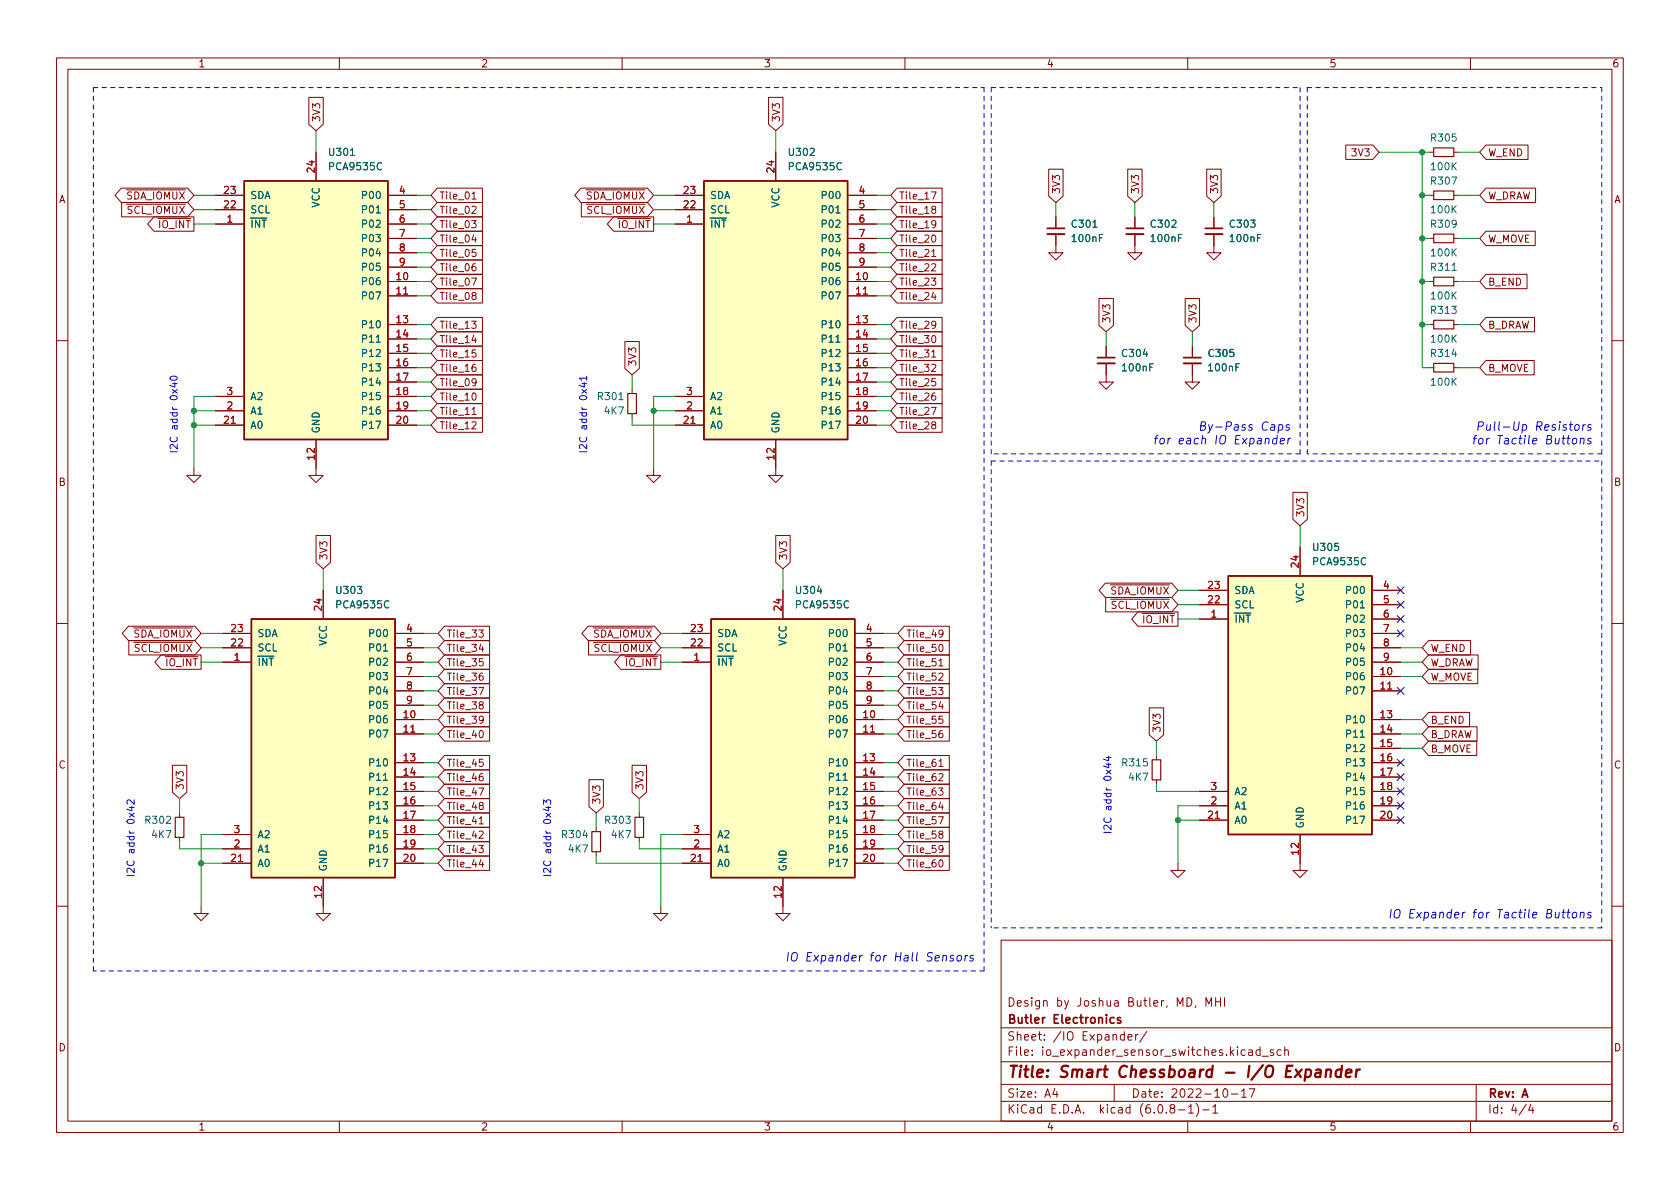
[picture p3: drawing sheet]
<svg xmlns="http://www.w3.org/2000/svg" width="297mm" height="210mm" viewBox="0 0 297 210" stroke-linecap="round" stroke-linejoin="round" font-family="sans-serif">
<defs><g id="words">
<text font-size="2.8" fill="#840000" x="178" y="190.6">Title: Smart Chessboard - I/O Expander</text>
<g font-size="2.1" fill="#0000c2">
<text x="214.7" y="76.2">By-Pass Caps</text>
<text x="264.5" y="76.2">Pull-Up Resistors</text>
<text x="207.6" y="78.6">for each IO Expander</text>
<text x="263.5" y="78.6">for Tactile Buttons</text>
<text x="250.6" y="162.4">IO Expander for Tactile Buttons</text>
<text x="143.8" y="170">IO Expander for Hall Sensors</text>
</g>
<g font-size="2.1" fill="#840000">
<text x="178" y="178">Design by Joshua Butler, MD, MHI</text>
<text x="178" y="184">Sheet: /IO Expander/</text>
<text x="178" y="181">Butler Electronics</text>
<text x="178" y="186.7">File: io_expander_sensor_switches.kicad_sch</text>
<text x="178" y="196.9">KiCad E.D.A. kicad (6.0.8-1)-1</text>
<text x="178" y="194.1">Size: A4</text>
<text x="200" y="194.1">Date: 2022-10-17</text>
<text x="263" y="194.1">Rev: A</text>
<text x="263" y="196.9">Id: 4/4</text>
</g>
<g font-size="1.8" fill="#840000">
<text x="35" y="11.9">1</text>
<text x="85" y="11.9">2</text>
<text x="135" y="11.9">3</text>
<text x="185" y="11.9">4</text>
<text x="235" y="11.9">5</text>
<text x="285" y="11.9">6</text>
<text x="56.6" y="21.7" transform="rotate(-90 56.6 21.7)">3V3</text>
<text x="137.9" y="21.7" transform="rotate(-90 137.9 21.7)">3V3</text>
<text x="239.3" y="27.6">3V3</text>
<text x="263.1" y="27.6">W_END</text>
<text x="10.3" y="35.9">A</text>
<text x="21" y="35.3">~{SDA_IOMUX}</text>
<text x="77.6" y="35.3">Tile_01</text>
<text x="102.2" y="35.3">~{SDA_IOMUX}</text>
<text x="158.9" y="35.3">Tile_17</text>
<text x="187.4" y="34.4" transform="rotate(-90 187.4 34.4)">3V3</text>
<text x="201.4" y="34.4" transform="rotate(-90 201.4 34.4)">3V3</text>
<text x="215.4" y="34.4" transform="rotate(-90 215.4 34.4)">3V3</text>
<text x="263.1" y="35.3">W_DRAW</text>
<text x="285.3" y="35.9">A</text>
<text x="21.2" y="37.8">~{SCL_IOMUX}</text>
<text x="26.7" y="40.3">~{IO_INT}</text>
<text x="77.6" y="40.3">Tile_03</text>
<text x="77.6" y="37.8">Tile_02</text>
<text x="102.4" y="37.8">~{SCL_IOMUX}</text>
<text x="108" y="40.3">~{IO_INT}</text>
<text x="158.9" y="37.8">Tile_18</text>
<text x="158.9" y="40.3">Tile_19</text>
<text x="77.6" y="42.9">Tile_04</text>
<text x="77.6" y="45.4">Tile_05</text>
<text x="77.6" y="48">Tile_06</text>
<text x="158.9" y="42.9">Tile_20</text>
<text x="158.9" y="45.4">Tile_21</text>
<text x="158.9" y="48">Tile_22</text>
<text x="263.1" y="42.9">W_MOVE</text>
<text x="77.6" y="50.5">Tile_07</text>
<text x="77.6" y="53">Tile_08</text>
<text x="158.9" y="50.5">Tile_23</text>
<text x="158.9" y="53">Tile_24</text>
<text x="263.1" y="50.5">B_END</text>
<text x="77.6" y="58.1">Tile_13</text>
<text x="158.9" y="58.1">Tile_29</text>
<text x="196.3" y="57.2" transform="rotate(-90 196.3 57.2)">3V3</text>
<text x="211.5" y="57.2" transform="rotate(-90 211.5 57.2)">3V3</text>
<text x="263.1" y="58.1">B_DRAW</text>
<text x="77.6" y="65.7">Tile_16</text>
<text x="77.6" y="60.7">Tile_14</text>
<text x="77.6" y="63.2">Tile_15</text>
<text x="112.5" y="64.9" transform="rotate(-90 112.5 64.9)">3V3</text>
<text x="158.9" y="60.7">Tile_30</text>
<text x="158.9" y="63.2">Tile_31</text>
<text x="158.9" y="65.7">Tile_32</text>
<text x="263.1" y="65.7">B_MOVE</text>
<text x="77.6" y="68.3">Tile_09</text>
<text x="77.6" y="70.8">Tile_10</text>
<text x="158.9" y="68.3">Tile_25</text>
<text x="158.9" y="70.8">Tile_26</text>
<text x="77.6" y="73.4">Tile_11</text>
<text x="77.6" y="75.9">Tile_12</text>
<text x="158.9" y="73.4">Tile_27</text>
<text x="158.9" y="75.9">Tile_28</text>
<text x="10.3" y="85.9">B</text>
<text x="285.3" y="85.9">B</text>
<text x="230.6" y="91.5" transform="rotate(-90 230.6 91.5)">3V3</text>
<text x="57.9" y="99.1" transform="rotate(-90 57.9 99.1)">3V3</text>
<text x="139.2" y="99.1" transform="rotate(-90 139.2 99.1)">3V3</text>
<text x="195" y="105.1">~{SDA_IOMUX}</text>
<text x="195.2" y="107.7">~{SCL_IOMUX}</text>
<text x="22.2" y="112.7">~{SDA_IOMUX}</text>
<text x="78.9" y="112.7">Tile_33</text>
<text x="103.5" y="112.7">~{SDA_IOMUX}</text>
<text x="160.2" y="112.7">Tile_49</text>
<text x="200.7" y="110.2">~{IO_INT}</text>
<text x="22.4" y="115.3">~{SCL_IOMUX}</text>
<text x="28" y="117.8">~{IO_INT}</text>
<text x="78.9" y="115.3">Tile_34</text>
<text x="78.9" y="117.8">Tile_35</text>
<text x="103.7" y="115.3">~{SCL_IOMUX}</text>
<text x="109.3" y="117.8">~{IO_INT}</text>
<text x="160.2" y="115.3">Tile_50</text>
<text x="160.2" y="117.8">Tile_51</text>
<text x="252.9" y="117.8">W_DRAW</text>
<text x="252.9" y="115.3">W_END</text>
<text x="78.9" y="120.4">Tile_36</text>
<text x="78.9" y="125.4">Tile_38</text>
<text x="78.9" y="122.9">Tile_37</text>
<text x="160.2" y="125.4">Tile_54</text>
<text x="160.2" y="122.9">Tile_53</text>
<text x="160.2" y="120.4">Tile_52</text>
<text x="252.9" y="120.4">W_MOVE</text>
<text x="78.9" y="128">Tile_39</text>
<text x="78.9" y="130.5">Tile_40</text>
<text x="160.2" y="130.5">Tile_56</text>
<text x="160.2" y="128">Tile_55</text>
<text x="205.2" y="129.6" transform="rotate(-90 205.2 129.6)">3V3</text>
<text x="252.9" y="128">B_END</text>
<text x="252.9" y="130.5">B_DRAW</text>
<text x="10.3" y="135.9">C</text>
<text x="78.9" y="135.6">Tile_45</text>
<text x="160.2" y="135.6">Tile_61</text>
<text x="252.9" y="133.1">B_MOVE</text>
<text x="285.3" y="135.9">C</text>
<text x="32.5" y="139.8" transform="rotate(-90 32.5 139.8)">3V3</text>
<text x="78.9" y="138.1">Tile_46</text>
<text x="78.9" y="143.2">Tile_48</text>
<text x="78.9" y="140.7">Tile_47</text>
<text x="106.1" y="142.3" transform="rotate(-90 106.1 142.3)">3V3</text>
<text x="113.8" y="139.8" transform="rotate(-90 113.8 139.8)">3V3</text>
<text x="160.2" y="138.1">Tile_62</text>
<text x="160.2" y="143.2">Tile_64</text>
<text x="160.2" y="140.7">Tile_63</text>
<text x="78.9" y="148.3">Tile_42</text>
<text x="78.9" y="145.8">Tile_41</text>
<text x="160.2" y="148.3">Tile_58</text>
<text x="160.2" y="145.8">Tile_57</text>
<text x="78.9" y="153.4">Tile_44</text>
<text x="78.9" y="150.8">Tile_43</text>
<text x="160.2" y="153.4">Tile_60</text>
<text x="160.2" y="150.8">Tile_59</text>
<text x="10.3" y="185.9">D</text>
<text x="285.3" y="185.9">D</text>
<text x="35" y="199.9">1</text>
<text x="85" y="199.9">2</text>
<text x="135" y="199.9">3</text>
<text x="185" y="199.9">4</text>
<text x="235" y="199.9">5</text>
<text x="285" y="199.9">6</text>
</g>
<g font-size="1.8" fill="#006464">
<text x="58.3" y="27.6">U301</text>
<text x="139.6" y="27.6">U302</text>
<text x="253.2" y="25">R305</text>
<text x="44.2" y="35.2">SDA</text>
<text x="58.4" y="30.1">PCA9535C</text>
<text x="64.4" y="35.2">P00</text>
<text x="125.5" y="35.2">SDA</text>
<text x="139.7" y="30.1">PCA9535C</text>
<text x="145.7" y="35.2">P00</text>
<text x="253.2" y="32.6">R307</text>
<text x="253.2" y="30.1">100K</text>
<text x="44.2" y="40.3">~{INT}</text>
<text x="44.2" y="37.7">SCL</text>
<text x="56.5" y="36.7" transform="rotate(-90 56.5 36.7)">VCC</text>
<text x="64.4" y="37.7">P01</text>
<text x="64.4" y="40.3">P02</text>
<text x="125.5" y="40.3">~{INT}</text>
<text x="125.5" y="37.7">SCL</text>
<text x="137.8" y="36.7" transform="rotate(-90 137.8 36.7)">VCC</text>
<text x="145.7" y="37.7">P01</text>
<text x="145.7" y="40.3">P02</text>
<text x="189.6" y="40.3">C301</text>
<text x="203.6" y="40.3">C302</text>
<text x="217.6" y="40.3">C303</text>
<text x="253.2" y="37.7">100K</text>
<text x="253.2" y="40.3">R309</text>
<text x="64.4" y="42.8">P03</text>
<text x="64.4" y="45.3">P04</text>
<text x="64.4" y="47.9">P05</text>
<text x="145.7" y="42.8">P03</text>
<text x="145.7" y="45.3">P04</text>
<text x="145.7" y="47.9">P05</text>
<text x="189.7" y="42.8">100nF</text>
<text x="203.7" y="42.8">100nF</text>
<text x="217.6" y="42.8">100nF</text>
<text x="253.2" y="45.3">100K</text>
<text x="253.2" y="47.9">R311</text>
<text x="64.4" y="50.4">P06</text>
<text x="64.4" y="53">P07</text>
<text x="145.7" y="50.4">P06</text>
<text x="145.7" y="53">P07</text>
<text x="253.2" y="53">100K</text>
<text x="64.4" y="58">P10</text>
<text x="145.7" y="58">P10</text>
<text x="253.2" y="55.5">R313</text>
<text x="64.4" y="60.6">P11</text>
<text x="64.4" y="63.1">P12</text>
<text x="64.4" y="65.7">P13</text>
<text x="145.7" y="60.6">P11</text>
<text x="145.7" y="63.1">P12</text>
<text x="145.7" y="65.7">P13</text>
<text x="198.5" y="63.1">C304</text>
<text x="198.6" y="65.7">100nF</text>
<text x="213.8" y="63.1">C305</text>
<text x="213.8" y="65.7">100nF</text>
<text x="253.2" y="60.6">100K</text>
<text x="253.2" y="63.1">R314</text>
<text x="44.2" y="70.7">A2</text>
<text x="64.4" y="68.2">P14</text>
<text x="64.4" y="70.7">P15</text>
<text x="105.8" y="70.7">R301</text>
<text x="125.5" y="70.7">A2</text>
<text x="145.7" y="68.2">P14</text>
<text x="145.7" y="70.7">P15</text>
<text x="253.2" y="68.2">100K</text>
<text x="44.2" y="73.3">A1</text>
<text x="44.2" y="75.8">A0</text>
<text x="56.5" y="76.7" transform="rotate(-90 56.5 76.7)">GND</text>
<text x="64.4" y="73.3">P16</text>
<text x="64.4" y="75.8">P17</text>
<text x="106.9" y="73.3">4K7</text>
<text x="125.5" y="73.3">A1</text>
<text x="125.5" y="75.8">A0</text>
<text x="137.8" y="76.7" transform="rotate(-90 137.8 76.7)">GND</text>
<text x="145.7" y="73.3">P16</text>
<text x="145.7" y="75.8">P17</text>
<text x="232.3" y="97.4">U305</text>
<text x="232.4" y="99.9">PCA9535C</text>
<text x="59.6" y="105">U303</text>
<text x="59.6" y="107.6">PCA9535C</text>
<text x="140.9" y="105">U304</text>
<text x="140.9" y="107.6">PCA9535C</text>
<text x="218.2" y="107.6">SCL</text>
<text x="218.2" y="105">SDA</text>
<text x="230.5" y="106.6" transform="rotate(-90 230.5 106.6)">VCC</text>
<text x="238.4" y="105">P00</text>
<text x="238.4" y="107.6">P01</text>
<text x="45.5" y="112.6">SDA</text>
<text x="65.7" y="112.6">P00</text>
<text x="126.7" y="112.6">SDA</text>
<text x="147" y="112.6">P00</text>
<text x="218.2" y="110.1">~{INT}</text>
<text x="238.4" y="110.1">P02</text>
<text x="238.4" y="112.6">P03</text>
<text x="45.5" y="117.7">~{INT}</text>
<text x="45.5" y="115.2">SCL</text>
<text x="57.8" y="114.2" transform="rotate(-90 57.8 114.2)">VCC</text>
<text x="65.7" y="115.2">P01</text>
<text x="65.7" y="117.7">P02</text>
<text x="126.7" y="117.7">~{INT}</text>
<text x="126.7" y="115.2">SCL</text>
<text x="139.1" y="114.2" transform="rotate(-90 139.1 114.2)">VCC</text>
<text x="147" y="115.2">P01</text>
<text x="147" y="117.7">P02</text>
<text x="238.4" y="115.2">P04</text>
<text x="238.4" y="117.7">P05</text>
<text x="65.7" y="120.3">P03</text>
<text x="65.7" y="122.8">P04</text>
<text x="65.7" y="125.3">P05</text>
<text x="147" y="120.3">P03</text>
<text x="147" y="122.8">P04</text>
<text x="147" y="125.3">P05</text>
<text x="238.4" y="120.3">P06</text>
<text x="238.4" y="122.8">P07</text>
<text x="65.7" y="127.9">P06</text>
<text x="65.7" y="130.4">P07</text>
<text x="147" y="127.9">P06</text>
<text x="147" y="130.4">P07</text>
<text x="238.4" y="127.9">P10</text>
<text x="238.4" y="130.4">P11</text>
<text x="65.7" y="135.5">P10</text>
<text x="147" y="135.5">P10</text>
<text x="198.6" y="135.5">R315</text>
<text x="238.4" y="133">P12</text>
<text x="238.4" y="135.5">P13</text>
<text x="65.7" y="138">P11</text>
<text x="65.7" y="140.6">P12</text>
<text x="65.7" y="143.1">P13</text>
<text x="147" y="138">P11</text>
<text x="147" y="140.6">P12</text>
<text x="147" y="143.1">P13</text>
<text x="199.7" y="138">4K7</text>
<text x="218.2" y="143.1">A1</text>
<text x="218.2" y="140.6">A2</text>
<text x="238.4" y="138">P14</text>
<text x="238.4" y="140.6">P15</text>
<text x="238.4" y="143.1">P16</text>
<text x="25.8" y="145.7">R302</text>
<text x="26.9" y="148.2">4K7</text>
<text x="45.5" y="148.2">A2</text>
<text x="65.7" y="145.7">P14</text>
<text x="65.7" y="148.2">P15</text>
<text x="99.5" y="148.2">R304</text>
<text x="107.1" y="145.7">R303</text>
<text x="108.2" y="148.2">4K7</text>
<text x="126.7" y="148.2">A2</text>
<text x="147" y="145.7">P14</text>
<text x="147" y="148.2">P15</text>
<text x="218.2" y="145.7">A0</text>
<text x="230.5" y="146.6" transform="rotate(-90 230.5 146.6)">GND</text>
<text x="238.4" y="145.7">P17</text>
<text x="45.5" y="150.7">A1</text>
<text x="45.5" y="153.3">A0</text>
<text x="57.8" y="154.2" transform="rotate(-90 57.8 154.2)">GND</text>
<text x="65.7" y="150.7">P16</text>
<text x="65.7" y="153.3">P17</text>
<text x="100.6" y="150.7">4K7</text>
<text x="126.7" y="150.7">A1</text>
<text x="126.7" y="153.3">A0</text>
<text x="139.1" y="154.2" transform="rotate(-90 139.1 154.2)">GND</text>
<text x="147" y="150.7">P16</text>
<text x="147" y="153.3">P17</text>
</g>
<g font-size="1.8" fill="#a90000">
<text x="39.7" y="34.3">23</text>
<text x="55.6" y="30.4" transform="rotate(-90 55.6 30.4)">24</text>
<text x="70.6" y="34.3">4</text>
<text x="120.9" y="34.3">23</text>
<text x="136.9" y="30.4" transform="rotate(-90 136.9 30.4)">24</text>
<text x="151.9" y="34.3">4</text>
<text x="39.7" y="36.8">22</text>
<text x="40.1" y="39.4">1</text>
<text x="70.6" y="36.8">5</text>
<text x="70.6" y="39.4">6</text>
<text x="70.6" y="41.9">7</text>
<text x="120.9" y="36.8">22</text>
<text x="121.4" y="39.4">1</text>
<text x="151.9" y="36.8">5</text>
<text x="151.9" y="39.4">6</text>
<text x="151.9" y="41.9">7</text>
<text x="70.6" y="44.4">8</text>
<text x="70.6" y="47">9</text>
<text x="151.9" y="44.4">8</text>
<text x="151.9" y="47">9</text>
<text x="70.1" y="49.5">10</text>
<text x="70.1" y="52.1">11</text>
<text x="151.4" y="49.5">10</text>
<text x="151.4" y="52.1">11</text>
<text x="70.1" y="57.1">13</text>
<text x="70.1" y="59.7">14</text>
<text x="151.4" y="57.1">13</text>
<text x="151.4" y="59.7">14</text>
<text x="70.1" y="62.2">15</text>
<text x="70.1" y="64.8">16</text>
<text x="151.4" y="62.2">15</text>
<text x="151.4" y="64.8">16</text>
<text x="40.1" y="69.8">3</text>
<text x="70.1" y="67.3">17</text>
<text x="70.1" y="69.8">18</text>
<text x="121.4" y="69.8">3</text>
<text x="151.4" y="67.3">17</text>
<text x="151.4" y="69.8">18</text>
<text x="39.7" y="74.9">21</text>
<text x="40.1" y="72.4">2</text>
<text x="70.1" y="72.4">19</text>
<text x="70.1" y="74.9">20</text>
<text x="120.9" y="74.9">21</text>
<text x="121.4" y="72.4">2</text>
<text x="151.4" y="72.4">19</text>
<text x="151.4" y="74.9">20</text>
<text x="55.6" y="81.2" transform="rotate(-90 55.6 81.2)">12</text>
<text x="136.9" y="81.2" transform="rotate(-90 136.9 81.2)">12</text>
<text x="229.6" y="100.3" transform="rotate(-90 229.6 100.3)">24</text>
<text x="56.9" y="107.9" transform="rotate(-90 56.9 107.9)">24</text>
<text x="138.2" y="107.9" transform="rotate(-90 138.2 107.9)">24</text>
<text x="213.6" y="106.7">22</text>
<text x="213.6" y="104.1">23</text>
<text x="244.6" y="104.1">4</text>
<text x="244.6" y="106.7">5</text>
<text x="40.9" y="111.8">23</text>
<text x="71.9" y="111.8">4</text>
<text x="122.2" y="111.8">23</text>
<text x="153.2" y="111.8">4</text>
<text x="214.1" y="109.2">1</text>
<text x="244.6" y="109.2">6</text>
<text x="244.6" y="111.8">7</text>
<text x="40.9" y="114.3">22</text>
<text x="41.4" y="116.8">1</text>
<text x="71.9" y="114.3">5</text>
<text x="71.9" y="116.8">6</text>
<text x="71.9" y="119.4">7</text>
<text x="122.2" y="114.3">22</text>
<text x="122.7" y="116.8">1</text>
<text x="153.2" y="114.3">5</text>
<text x="153.2" y="116.8">6</text>
<text x="153.2" y="119.4">7</text>
<text x="244.1" y="119.4">10</text>
<text x="244.6" y="114.3">8</text>
<text x="244.6" y="116.8">9</text>
<text x="71.9" y="121.9">8</text>
<text x="71.9" y="124.5">9</text>
<text x="153.2" y="121.9">8</text>
<text x="153.2" y="124.5">9</text>
<text x="244.1" y="121.9">11</text>
<text x="71.4" y="127">10</text>
<text x="71.4" y="129.5">11</text>
<text x="152.7" y="127">10</text>
<text x="152.7" y="129.5">11</text>
<text x="244.1" y="127">13</text>
<text x="244.1" y="129.5">14</text>
<text x="71.4" y="134.6">13</text>
<text x="71.4" y="137.2">14</text>
<text x="152.7" y="134.6">13</text>
<text x="152.7" y="137.2">14</text>
<text x="244.1" y="132.1">15</text>
<text x="244.1" y="134.6">16</text>
<text x="244.1" y="137.2">17</text>
<text x="71.4" y="139.7">15</text>
<text x="71.4" y="142.2">16</text>
<text x="152.7" y="139.7">15</text>
<text x="152.7" y="142.2">16</text>
<text x="214.1" y="142.2">2</text>
<text x="214.1" y="139.7">3</text>
<text x="244.1" y="139.7">18</text>
<text x="244.1" y="142.2">19</text>
<text x="41.4" y="149.9">2</text>
<text x="41.4" y="147.3">3</text>
<text x="71.4" y="144.8">17</text>
<text x="71.4" y="147.3">18</text>
<text x="71.4" y="149.9">19</text>
<text x="122.7" y="149.9">2</text>
<text x="122.7" y="147.3">3</text>
<text x="152.7" y="144.8">17</text>
<text x="152.7" y="147.3">18</text>
<text x="152.7" y="149.9">19</text>
<text x="213.6" y="144.8">21</text>
<text x="244.1" y="144.8">20</text>
<text x="40.9" y="152.4">21</text>
<text x="71.4" y="152.4">20</text>
<text x="122.2" y="152.4">21</text>
<text x="152.7" y="152.4">20</text>
<text x="229.6" y="151.1" transform="rotate(-90 229.6 151.1)">12</text>
<text x="56.9" y="158.7" transform="rotate(-90 56.9 158.7)">12</text>
<text x="138.2" y="158.7" transform="rotate(-90 138.2 158.7)">12</text>
</g>
<g font-size="1.8" fill="#0000c2">
<text x="31.4" y="80.3" transform="rotate(-90 31.4 80.3)">I2C addr 0x40</text>
<text x="103.8" y="80.3" transform="rotate(-90 103.8 80.3)">I2C addr 0x41</text>
<text x="196.5" y="147.6" transform="rotate(-90 196.5 147.6)">I2C addr 0x44</text>
<text x="23.8" y="155.2" transform="rotate(-90 23.8 155.2)">I2C addr 0x42</text>
<text x="97.4" y="155.2" transform="rotate(-90 97.4 155.2)">I2C addr 0x43</text>
</g>
</g></defs>
<g fill="none" stroke="#840000" stroke-width=".18">
<path d="M10 10.2h277v190.1h-277zM12 12.2h273v186.1h-273zM54.6 17.2h2.6v4.8l-1.3 1.1-1.3-1.1zM60 10.2v2M110 10.2v2M135.9 17.2h2.5v4.8l-1.2 1.1-1.3-1.1zM160 10.2v2M210 10.2v2M260 10.2v2M21.4 33.3h11.8l1.1 1.2-1.1 1.3h-11.8l-1.1-1.3zM21.5 35.8h11.7l1.1 1.3-1.1 1.2h-11.7zM27.2 38.3h7.1v2.6h-7.1l-1.1-1.3z"/>
<path d="M38.1 39.6h5.1M38.1 37.1h5.1M38.1 34.5h5.1M55.9 26.9v5.1M68.6 39.6h5.1M68.6 37.1h5.1M68.6 34.5h5.1M77.3 38.3h8v2.6h-8l-1.1-1.3zM77.3 35.8h8v2.5h-8l-1.1-1.2zM77.3 33.3h8v2.5h-8l-1.1-1.3zM83.4 39h.8l-.4 .5 .3 .1v.6l-.2 .1-.5-.1M83.5 36.6l.4-.1 .3 .3-.8 .9h.8"/>
<path d="M83.5 34.3l.3-.4v1.3M83.5 35.2h.7M102.7 33.3h11.8l1.1 1.2-1.1 1.3h-11.8l-1.1-1.3zM102.8 35.8h11.7l1.1 1.3-1.1 1.2h-11.7zM108.5 38.3h7.1v2.6h-7.1l-1.1-1.3zM119.4 39.6h5.1M119.4 37.1h5.1M119.4 34.5h5.1M137.2 26.9v5.1M149.9 39.6h5M149.9 37.1h5M149.9 34.5h5"/>
<path d="M158.6 33.3h8v2.5h-8l-1.1-1.3zM158.6 35.8h8v2.5h-8l-1.1-1.2zM158.6 38.3h8v2.6h-8l-1.1-1.3zM164.7 33.9h.8l-.5 1.3M165 37l-.3-.2 .1-.2 .2-.1h.3l.2 .2-.1 .2-.5 .2-.2 .2v.2l.3 .2h.2l.3-.2-.1-.4-.2-.1M165.5 39.6l-.3 .2h-.2l-.3-.2 .2-.5 .3-.1 .2 .1a.84 .84 0 0 1-.3 1.2h-.2M185.4 29.9h2.6v4.8l-1.3 1.1-1.3-1.1zM186.7 38.3v2.1M199.4 29.9h2.5v4.8l-1.2 1.1-1.3-1.1zM200.7 38.3v2.1M213.4 29.9h2.5v4.8l-1.3 1.1-1.2-1.1zM214.6 38.3v2.1"/>
<path d="M238 25.6h4.7l1.1 1.3-1.1 1.3h-4.7zM252.7 34.5h.8M252.7 26.9h.8M257 34.5h.8M257 26.9h.8M262.7 25.6h7.5v2.6h-7.5l-1.1-1.3zM262.7 33.3h8.8v2.5h-8.8l-1.1-1.3zM68.6 49.8h5.1M68.6 52.3h5.1M68.6 57.4h5.1M68.6 59.9h5.1M68.6 42.2h5.1"/>
<path d="M68.6 44.7h5.1M68.6 47.2h5.1M77.3 40.9h8v2.5h-8l-1.1-1.2zM77.3 43.4h8v2.6h-8l-1.1-1.3zM77.3 48.5h8v2.5h-8l-1.1-1.2zM77.3 56.1h8v2.6h-8l-1.1-1.3zM77.3 46h8v2.5h-8l-1.1-1.3zM77.3 51h8v2.6h-8l-1.1-1.3zM77.3 58.7h8v2.5h-8l-1.1-1.3zM83.4 49.2h.8l-.5 1.2M83.4 56.8h.8l-.4 .5 .3 .1v.5l-.2 .2-.5-.2M83.7 52.3l-.2-.3v-.2l.2-.1 .4 .1 .1 .2-.1 .1-.5 .2-.1 .2v.4l.2 .1h.2l.3-.3-.1-.3-.2-.1"/>
<path d="M83.8 41.5l-.3 .9h.7M83.8 59.3l-.3 .9h.7M84.1 46.6l-.4 .1a.86 .86 0 0 0 0 1.2l.4-.1 .1-.4-.3-.3h-.2l-.2 .3M84.1 42v.8M84.1 59.8v.8M84.1 44.1h-.6v.6l.1-.1h.5l.1 .2-.1 .4-.2 .2-.4-.2M149.9 49.8h5M149.9 52.3h5M149.9 57.4h5M149.9 59.9h5M149.9 42.2h5M149.9 44.7h5"/>
<path d="M149.9 47.2h5M158.6 58.7h8v2.5h-8l-1.1-1.3zM158.6 40.9h8v2.5h-8l-1.1-1.2zM158.6 43.4h8v2.6h-8l-1.1-1.3zM158.6 48.5h8v2.5h-8l-1.1-1.2zM158.6 46h8v2.5h-8l-1.1-1.3zM158.6 56.1h8v2.6h-8l-1.1-1.3zM158.6 51h8v2.6h-8l-1.1-1.3zM164.7 49.2h.8l-.5 .5 .4 .1v.5l-.2 .1-.5-.1M164.7 44.5l.4-.4v1.3M164.7 46.8l.5-.2 .3 .4-.8 .9h.8M164.7 45.4h.8"/>
<path d="M164.9 59.5l.1-.2a.68 .68 0 0 1 .5 .7 .68 .68 0 0 1-.5 .6l-.1-.1-.2-.4zM164.9 41.7l.1-.1a.68 .68 0 0 1 .5 .6 .68 .68 0 0 1-.5 .6l-.1-.1-.2-.4zM165 51.7l-.3 .9h.8M165.3 52.1v.9M165.5 57.3l-.3 .3h-.2l-.3-.3 .2-.4 .3-.1 .2 .1a.84 .84 0 0 1-.3 1.2h-.2M186.7 41.4v3.3h1.3l-1.3 1.3-1.3-1.3h1.3M194.3 52.8h2.6v4.8l-1.3 1.1-1.3-1.1zM200.7 41.4v3.3h1.2l-1.2 1.3-1.3-1.3h1.3M209.5 52.8h2.6v4.8l-1.3 1.1-1.3-1.1zM214.6 41.4v3.3h1.3l-1.3 1.3-1.2-1.3h1.2M252.7 49.8h.8M252.7 57.4h.8"/>
<path d="M252.7 42.2h.8M257 49.8h.8M257 57.4h.8M257 42.2h.8M262.7 48.5h7.3v2.5h-7.3l-1.1-1.2zM262.7 56.1h8.6v2.6h-8.6l-1.1-1.3zM262.7 40.9h8.7v2.5h-8.7l-1.1-1.2zM10 60.2h2M38.1 70.1h5.1M38.1 72.6h5.1M38.1 75.2h5.1M55.9 77.7v6.4h1.2l-1.2 1.2-1.3-1.2h1.3"/>
<path d="M68.6 62.5h5.1M68.6 65h5.1M68.6 67.6h5.1M68.6 70.1h5.1M68.6 72.6h5.1M68.6 75.2h5.1M77.3 71.4h8v2.5h-8l-1.1-1.3zM77.3 73.9h8v2.5h-8l-1.1-1.2zM77.3 63.7h8v2.6h-8l-1.1-1.3zM77.3 66.3h8v2.5h-8l-1.1-1.2zM77.3 61.2h8v2.5h-8l-1.1-1.2zM77.3 68.8h8v2.6h-8l-1.1-1.3z"/>
<path d="M83.5 72.4l.3-.4v1.3M83.5 74.7l.4-.1 .3 .3-.8 .9h.8M83.5 73.3h.7M83.6 69.6l.2-.1a.68 .68 0 0 1 .4 .6 .68 .68 0 0 1-.4 .7l-.2-.2-.1-.3zM84.1 64.4l-.4 .1a.86 .86 0 0 0 0 1.2l.4-.1 .1-.5-.3-.2h-.2l-.2 .2M84.1 61.9h-.6v.6l.1-.1h.5l.1 .2-.1 .4-.2 .1-.4-.1M84.2 67.5l-.3 .2h-.2l-.2-.2 .1-.5h.3l.2 .1a.84 .84 0 0 1-.3 1.1h-.2M110.5 60.4h2.5v4.8l-1.2 1.1-1.3-1.1zM111.8 68.8v.8M111.8 73.1v.8M119.4 70.1h5.1M119.4 72.6h5.1"/>
<path d="M119.4 75.2h5.1M137.2 77.7v6.4h1.2l-1.2 1.2-1.3-1.2h1.3M149.9 62.5h5M149.9 65h5M149.9 67.6h5M149.9 70.1h5M149.9 72.6h5M149.9 75.2h5M158.6 66.3h8v2.5h-8l-1.1-1.2zM158.6 61.2h8v2.5h-8l-1.1-1.2zM158.6 63.7h8v2.6h-8l-1.1-1.3zM158.6 68.8h8v2.6h-8l-1.1-1.3z"/>
<path d="M158.6 71.4h8v2.5h-8l-1.1-1.3zM158.6 73.9h8v2.5h-8l-1.1-1.2zM164.7 72h.8l-.5 1.3M164.7 62.2l.4-.3v1.2M164.7 64.5l.5-.1 .3 .4-.8 .9h.8M164.7 63.1h.8M165 75.1l-.3-.2 .1-.2 .2-.1h.3l.2 .2-.1 .2-.5 .2-.2 .2 .1 .3 .2 .1h.2l.3-.2-.1-.4-.2-.1M165.3 69.5l-.3 .1a.86 .86 0 0 0 0 1.2l.4-.2 .1-.4-.3-.2h-.2l-.3 .2M165.4 67h-.6l-.1 .6 .2-.2 .4 .1 .2 .2-.1 .4-.2 .1-.5-.1M195.6 64.3v3.3h1.2l-1.2 1.2-1.3-1.2h1.3M195.6 61.2v2M210.8 64.3v3.3h1.3l-1.3 1.2-1.3-1.2h1.3"/>
<path d="M210.8 61.2v2M252.7 65h.8M257 65h.8M262.7 63.7h8.6v2.6h-8.6l-1.1-1.3zM285 60.2h2M34.3 82.8v1.3h1.3l-1.3 1.2-1.3-1.2h1.3M55.9 94.7h2.5v4.8l-1.3 1.1-1.2-1.1zM115.6 82.8v1.3h1.2l-1.2 1.2-1.3-1.2h1.3M137.2 94.7h2.5v4.8l-1.3 1.1-1.2-1.1zM228.6 87.1h2.5v4.7l-1.2 1.2-1.3-1.2zM229.9 96.8v5M10 110.2h2"/>
<path d="M22.7 110.7h11.7l1.2 1.3-1.2 1.3h-11.7l-1.1-1.3zM22.8 113.3h11.6l1.2 1.2-1.2 1.3h-11.6zM28.5 115.8h7.1v2.6h-7.1l-1.1-1.3zM39.4 117.1h5M39.4 114.5h5M39.4 112h5M57.1 104.4v5.1M69.8 117.1h5.1M69.8 114.5h5.1M69.8 112h5.1M69.8 119.6h5.1M78.6 113.3h8v2.5h-8l-1.1-1.3z"/>
<path d="M78.6 115.8h8v2.6h-8l-1.1-1.3zM78.6 118.4h8v2.5h-8l-1.1-1.3zM78.6 110.7h8v2.6h-8l-1.1-1.3zM84.7 111.4h.7l-.4 .5 .4 .1v.6l-.2 .1-.5-.1M85 113.9l-.3 .9h.8M85.3 119l-.3 .1a.86 .86 0 0 0 0 1.2l.4-.1v-.5l-.2-.2h-.2l-.3 .2M85.3 114.4v.8M85.4 116.5h-.6l-.1 .6 .2-.1h.4l.1 .2v.4l-.2 .2-.5-.2M104 110.7h11.7l1.1 1.3-1.1 1.3h-11.7l-1.1-1.3zM104.1 113.3h11.6l1.1 1.2-1.1 1.3h-11.6zM109.8 115.8h7v2.6h-7l-1.1-1.3zM120.6 117.1h5.1"/>
<path d="M120.6 114.5h5.1M120.6 112h5.1M138.4 104.4v5.1M151.1 117.1h5.1M151.1 114.5h5.1M151.1 112h5.1M151.1 119.6h5.1M159.9 113.3h7.9v2.5h-7.9l-1.2-1.3zM159.9 115.8h7.9v2.6h-7.9l-1.2-1.3zM159.9 118.4h7.9v2.5h-7.9l-1.2-1.3zM159.9 110.7h7.9v2.6h-7.9l-1.2-1.3zM166 116.8l.4-.3v1.3"/>
<path d="M166 119.1l.5-.1 .2 .4-.8 .9h.8M166 117.8h.7M166.1 114.1l.2-.2a.68 .68 0 0 1 .4 .7 .68 .68 0 0 1-.4 .6l-.2-.1-.1-.4zM166.7 111.9l-.2 .3h-.3l-.2-.3 .1-.4 .4-.1 .2 .1a.84 .84 0 0 1-.3 1.2h-.3M195.4 103.1h11.8l1.1 1.3-1.1 1.3h-11.8l-1.1-1.3zM195.5 105.7h11.7l1.1 1.2-1.1 1.3h-11.7zM201.2 108.2h7.1v2.5h-7.1l-1.1-1.2zM212.1 109.5h5.1M212.1 106.9h5.1M212.1 104.4h5.1M242.6 117.1h5M242.6 114.5h5"/>
<path d="M242.6 112h5M242.6 119.6h5M242.6 109.5h5M242.6 106.9h5M242.6 104.4h5M252.6 118.4h8.7v2.5h-8.7l-1.1-1.3zM252.6 115.8h8.7v2.6h-8.7l-1.1-1.3zM252.6 113.3h7.4v2.5h-7.4l-1.1-1.3zM285 110.2h2M30.5 135.3h2.5v4.8l-1.3 1.1-1.2-1.1zM69.8 127.2h5.1M69.8 129.8h5.1"/>
<path d="M69.8 134.9h5.1M69.8 137.4h5.1M69.8 139.9h5.1M69.8 122.2h5.1M69.8 124.7h5.1M78.6 123.4h8v2.6h-8l-1.1-1.3zM78.6 120.9h8v2.5h-8l-1.1-1.2zM78.6 136.1h8v2.6h-8l-1.1-1.3zM78.6 126h8v2.5h-8l-1.1-1.3zM78.6 128.5h8v2.6h-8l-1.1-1.3zM78.6 133.6h8v2.5h-8l-1.1-1.2zM78.6 138.7h8v2.5h-8l-1.1-1.3z"/>
<path d="M84.7 121.6h.8l-.5 1.2M84.7 139.3h.8l-.5 1.3M84.8 129.3l.2-.1a.68 .68 0 0 1 .5 .6 .68 .68 0 0 1-.5 .7l-.2-.2-.1-.3zM85 124.6l-.3-.2 .1-.2 .2-.1 .3 .1 .1 .1v.2l-.6 .2-.1 .2 .1 .4 .2 .1h.2l.2-.3v-.3l-.2-.2M85.3 136.8l-.3 .1a.86 .86 0 0 0 0 1.2l.4-.1v-.5l-.2-.2h-.2l-.3 .2M85.4 134.3h-.6l-.1 .6 .2-.2 .4 .1 .1 .2v.4l-.2 .1-.5-.1M85.4 127.2l-.2 .2h-.2l-.3-.2 .1-.5 .4-.1 .2 .2a.84 .84 0 0 1-.3 1.1h-.3M104.1 137.9h2.6v4.7l-1.3 1.2-1.3-1.2zM111.8 135.3h2.5v4.8l-1.3 1.1-1.2-1.1zM151.1 127.2h5.1M151.1 129.8h5.1M151.1 134.9h5.1"/>
<path d="M151.1 137.4h5.1M151.1 139.9h5.1M151.1 122.2h5.1M151.1 124.7h5.1M159.9 136.1h7.9v2.6h-7.9l-1.2-1.3zM159.9 133.6h7.9v2.5h-7.9l-1.2-1.2zM159.9 128.5h7.9v2.6h-7.9l-1.2-1.3zM159.9 138.7h7.9v2.5h-7.9l-1.2-1.3zM159.9 126h7.9v2.5h-7.9l-1.2-1.3zM159.9 123.4h7.9v2.6h-7.9l-1.2-1.3zM159.9 120.9h7.9v2.5h-7.9l-1.2-1.2zM165.9 139.3h.8l-.4 .5 .4 .1v.6l-.2 .1-.6-.1"/>
<path d="M165.9 121.6h.8l-.4 .4 .4 .2v.5l-.2 .1-.6-.1M166 136.9l.5-.1 .2 .4-.8 .9h.8M166 134.6l.4-.3v1.2M166 135.5h.7M166.3 124l-.3 1h.8M166.6 129.2h-.4a.86 .86 0 0 0 0 1.3l.5-.2v-.4l-.2-.2h-.3l-.2 .2M166.6 124.5v.9M166.7 126.6h-.6l-.1 .6 .2-.1 .4 .1 .1 .2v.4l-.2 .1-.5-.1M203.2 125.2h2.5v4.7l-1.2 1.2-1.3-1.2zM204.5 133.6v.8M204.5 137.9v.8M212.1 139.9h5.1"/>
<path d="M242.6 127.2h5M242.6 129.8h5M242.6 134.9h5M242.6 137.4h5M242.6 139.9h5M242.6 122.2h5M242.6 132.3h5M252.6 126h7.2v2.5h-7.2l-1.1-1.3zM252.6 131.1h8.5v2.5h-8.5l-1.1-1.3zM252.6 128.5h8.6v2.6h-8.6l-1.1-1.3zM31.7 143.8v.7M31.7 148.1v.7"/>
<path d="M39.4 147.6h5M39.4 150.1h5M39.4 152.6h5M57.1 155.2v6.3h1.3l-1.3 1.3-1.2-1.3h1.2M69.8 142.5h5.1M69.8 145h5.1M69.8 147.6h5.1M69.8 150.1h5.1M69.8 152.6h5.1M78.6 146.3h8v2.5h-8l-1.1-1.2zM78.6 151.4h8v2.5h-8l-1.1-1.3zM78.6 148.8h8v2.6h-8l-1.1-1.3z"/>
<path d="M78.6 143.8h8v2.5h-8l-1.1-1.3zM78.6 141.2h8v2.6h-8l-1.1-1.3zM84.7 149.5h.7l-.4 .5 .4 .1v.6l-.2 .1-.5-.1M84.7 147.1l.5-.1 .2 .3-.7 .9h.7M84.7 144.8l.4-.4v1.3M84.7 145.7h.7M85 142.4l-.3-.2 .1-.2 .2-.1h.3l.1 .2v.2l-.6 .2-.1 .2 .1 .3 .2 .2h.2l.2-.3v-.4l-.2-.1M85 152l-.3 .9h.8M85.3 152.5v.8M105.4 146.3v.8M105.4 150.6v.8M113 143.8v.7"/>
<path d="M113 148.1v.7M120.6 147.6h5.1M120.6 150.1h5.1M120.6 152.6h5.1M138.4 155.2v6.3h1.3l-1.3 1.3-1.2-1.3h1.2M151.1 142.5h5.1M151.1 145h5.1M151.1 147.6h5.1M151.1 150.1h5.1M151.1 152.6h5.1M159.9 141.2h7.9v2.6h-7.9l-1.2-1.3zM159.9 151.4h7.9v2.5h-7.9l-1.2-1.3z"/>
<path d="M159.9 146.3h7.9v2.5h-7.9l-1.2-1.2zM159.9 148.8h7.9v2.6h-7.9l-1.2-1.3zM159.9 143.8h7.9v2.5h-7.9l-1.2-1.3zM165.9 144.4h.9l-.6 1.3M166.1 152.2l.2-.2a.68 .68 0 0 1 .4 .7 .68 .68 0 0 1-.4 .6l-.2-.1-.1-.4zM166.2 147.5l-.2-.2 .1-.2 .1-.1h.4l.1 .2v.2l-.6 .2-.1 .1 .1 .4 .1 .1h.3l.2-.2v-.4l-.2-.1M166.3 141.8l-.3 .9h.8M166.6 142.3v.9M166.7 150l-.2 .3h-.3l-.2-.3 .1-.4 .4-.1 .2 .1a.84 .84 0 0 1-.3 1.2h-.3M208.3 152.6v1.3h1.2l-1.2 1.3-1.3-1.3h1.3M212.1 142.5h5.1M212.1 145h5.1"/>
<path d="M229.9 147.6v6.3h1.2l-1.2 1.3-1.3-1.3h1.3M242.6 142.5h5M242.6 145h5M10 160.2h2M35.6 160.3v1.2h1.2l-1.2 1.3-1.3-1.3h1.3M116.8 160.3v1.2h1.3l-1.3 1.3-1.2-1.3h1.2M177 166.3h108v32h-108zM209.9 176.4a.76 .76 0 0 1 .8 .8 .76 .76 0 0 1-.8 .7zM211.4 177.9l-.1 .2M213.2 177.9v-1.5l.5 1.1 .5-1.1v1.5M214.9 176.4v1.5M214.9 177.1h.9"/>
<path d="M215.8 176.4v1.5M216.5 176.4v1.5M285 160.2h2M60 198.3v2M110 198.3v2M160 198.3v2M177 194.8h108M177 191.8h108M177 187.8h108M177 181.8h108M186.5 192.5l-.4 1h1M186.9 193v1"/>
<path d="M197 191.8v3M198.8 183l-.4-.1-.3 .3v.4l.1 .3h.6M198.8 182.4v1.5M199.4 183.4l.7-.1v-.3l-.5-.1-.2 .2 .1 .8h.6M200.8 182.9v1M201.2 182.9l-.3 .1-.1 .2M202.8 182.4l-1.3 1.9M207.1 196l-.2-.3v-.2l.2-.2 .5 .1 .1 .2-.1 .2-.6 .2-.1 .3v.4l.2 .1h.5l.1-.3-.1-.4-.2-.1M208.4 196.3h1.1M210 198.3v2M210.1 195.8l.5-.5v1.5M210.1 196.8h.9"/>
<path d="M211.5 195.1a1.72 1.72 0 0 1 0 2.3M212.6 196.3h1.2M214.4 195.8l.5-.5v1.5M214.4 196.8h.9M216.4 192.6l.2-.1a.81 .81 0 0 1 .6 .7 .81 .81 0 0 1-.3 .8h-.2a.81 .81 0 0 1-.6-.6 .81 .81 0 0 1 .3-.8zM217.7 193.5h1.2M219.5 193l.4-.5v1.5M219.5 194h.9M220.8 185.7h.6v.9M220.9 192.5h1l-.7 1.5M221.4 186l-.5 .1a.29 .29 0 0 0-.2 .2 .29 .29 0 0 0 .2 .3h.5M222.8 185.7l-.4-.1-.3 .3v.4l.1 .3h.6"/>
<path d="M222.8 185.1v1.5M223.1 186.8h1.2M225.1 185.7l-.3-.1-.2 .2v.3l.5 .1v.4h-.5M226.5 185.7l-.4-.1-.3 .3v.4l.1 .3h.6M227.1 185.8l.3-.2 .3 .1 .1 .9M227.1 185.1v1.5M260 198.3v2M261 191.8v6.5M269.9 195.3l-1.3 1.9M270.6 195.3l-.3 1h.9M271 195.8v1"/>
</g>
<path d="M230.9 189.2l.2-.1 .6 .1 .1 .3v.6a.66 .66 0 0 1-1 .3M232.7 189.2l.2-.1 .6 .1-.1 1.3M233.5 189.6l-.7 .1a.4 .4 0 0 0-.3 .3 .4 .4 0 0 0 .3 .5l.6-.1M234.5 189.3a.49 .49 0 0 1 .9 .1l-.2 1.1M234.5 189.1l-.1 1.4M237.2 189.2a.66 .66 0 0 0-1 .3l-.1 .6 .2 .3 .2 .1 .5-.1M237.3 188.5l-.3 2M238 189.8l1-.2-.1-.4-.2-.1-.6 .1-.2 1 .3 .3 .6-.1M239.9 189.1l-.2 1.4M240.4 189.1l-.4 .1-.2 .3" fill="none" stroke="#840000" stroke-width=".4"/>
<path d="M185.2 40.4h3M199.1 40.4h3.1M213.1 40.4h3.1M194.1 63.2h3M209.3 63.2h3M197 180l-.4-.1-.3 .3v.4l.1 .3h.6M198.1 180l-.3-.1-.2 .2v.3l.5 .1v.4h-.5" fill="none" stroke="#840000" stroke-width=".3"/>
<g fill="#ffffc2" stroke="#ffffc2" stroke-width=".18">
<path d="M124.5 32h25.4v45.7h-25.4z"/>
<path d="M125.7 109.5h25.4v45.7h-25.4z"/>
<path d="M44.4 109.5h25.4v45.7h-25.4z"/>
<path d="M43.2 32h25.4v45.7h-25.4z"/>
<path d="M217.2 101.8h25.4v45.8h-25.4z"/>
</g>
<path d="M43.2 32h25.4v45.7h-25.4zM124.5 32h25.4v45.7h-25.4zM44.4 109.5h25.4v45.7h-25.4zM125.7 109.5h25.4v45.7h-25.4zM217.2 101.8h25.4v45.8h-25.4z" fill="none" stroke="#840000" stroke-width=".25"/>
<path d="M253.5 33.8h3.5v1.5h-3.5zM253.5 26.2h3.5v1.5h-3.5zM253.5 41.4h3.5v1.5h-3.5zM253.5 49h3.5v1.5h-3.5zM253.5 56.6h3.5v1.6h-3.5zM111 69.6h1.5v3.5h-1.5zM253.5 64.3h3.5v1.5h-3.5zM203.7 134.4h1.5v3.5h-1.5zM31 144.5h1.5v3.6h-1.5zM104.6 147.1h1.6v3.5h-1.6zM112.3 144.5h1.5v3.6h-1.5z" fill="none" stroke="#840000" stroke-width=".2"/>
<path d="M185.2 41.4h3M199.1 41.4h3.1M213.1 41.4h3.1M194.1 64.3h3M209.3 64.3h3" fill="none" stroke="#840000" stroke-width=".33"/>
<g fill="none" stroke="#0000c2" stroke-width=".18">
<path d="M30.2 66.6a.69 .69 0 0 1 1.1 .3 .72 .72 0 0 1-1.2-.1zM30.5 67.8h.8M30.9 67.7v.7l-.9-.3M102.9 67.8h.8M102.9 68.9l.8 .6M103.3 67.7v.7l-.9-.3M103.7 66.9h-1.2l.3 .3M103.7 68.9l-.8 .6M103.7 66.5v.7M204.1 77.5h.6M204.8 77l-.4 .2-.2 1.3M205.2 77.6l.2-.1 .4 .1v.6l-.1 .2-.4 .1-.2-.1z"/>
<path d="M206.6 77.5l-.2 1M207 77.5l-.3 .1-.2 .2M212.3 75.3l.7-.1 .2-.2-.1-.3-.2-.1h-.5l-.2 1.5h.6l.2-.2 .2-.3-.4-.3M213.7 75.1l.2 1M214.4 75.1l-.6 1.3-.3 .2M260.5 77.5h.6M261.1 77l-.4 .2-.1 1.3M261.4 75.4l.7-.1 .2-.2-.1-.4-.2-.1h-.5l-.2 1.5M261.5 77.6l.3-.1 .4 .1v.6l-.2 .2-.4 .1-.2-.1zM262.9 75.1v.9l.3 .1 .2-.2M262.9 77.5l-.1 1M263.3 77.5l-.3 .1-.1 .2"/>
<path d="M263.6 75.1l-.2 1M281.3 77.6a.37 .37 0 0 0-.6 .2l.1 .1 .5 .2v.2l-.2 .2-.4-.1M195.6 135.2h.8M195.6 133.9h.8M196 135v.8l-.9-.3M196 133.8v.8l-.9-.4M22.9 142.8h.8M23.3 142.6v.8l-.9-.3M23.7 141.4v.8l-.9-.8-.3 .3 .1 .5M96.1 142.2v-.8l.5 .5 .1-.4h.6l.1 .2-.1 .5M96.5 142.8h.9M97 142.6v.8l-1-.3"/>
<path d="M139.4 168.4l-.2 1.5M140.1 168.7a.52 .52 0 0 1 .8 0 1.1 1.1 0 0 1-.4 1.2h-.4a1.12 1.12 0 0 1 0-1.2zM142.7 169.2h.5M143.5 168.4h-.7l-.2 1.5h.8M172.1 169a.37 .37 0 0 0-.6 .2l.1 .2 .4 .1 .1 .2-.2 .2h-.5M246 160.8l-.2 1.5M246.7 161a.52 .52 0 0 1 .8 0 1.1 1.1 0 0 1-.4 1.3h-.4a1.12 1.12 0 0 1 0-1.3zM249.3 161.5h.5M250.1 160.8h-.7l-.2 1.5h.7M281.3 161.4a.37 .37 0 0 0-.6 .2l.1 .2 .5 .1v.2l-.2 .2h-.4"/>
</g>
<g fill="none" stroke="#0000c2" stroke-width=".18" stroke-dasharray=".8 .8">
<path d="M16.5 15.5v156.2M16.5 15.5h157.5M174 15.5v156.2M175.3 15.5v64.8M175.3 15.5h54.6M229.9 15.5v64.8M231.1 15.5v64.8M231.1 15.5h52.1M283.2 15.5v64.8M175.3 81.5v82.6M175.3 81.5h107.9M229.9 80.3h-54.6"/>
<path d="M283.2 80.3h-52.1M283.2 81.5v82.6M174 171.7h-157.5M283.2 164.1h-107.9"/>
</g>
<g fill="none" stroke="#009600" stroke-width=".18">
<path d="M34.3 34.5h3.8M34.3 39.6h3.8M34.3 37.1h3.8M55.9 23.1v3.8M73.7 34.5h2.5M73.7 39.6h2.5M73.7 37.1h2.5M115.6 34.5h3.8M115.6 39.6h3.8M115.6 37.1h3.8M137.2 23.1v3.8M154.9 34.5h2.6"/>
<path d="M154.9 39.6h2.6M154.9 37.1h2.6M186.7 35.8v2.5M200.7 35.8v2.5M214.6 35.8v2.5M243.8 26.9h8.9M251.5 34.5h1.2M251.5 26.9v38.1h1.2M257.8 34.5h3.8M257.8 26.9h3.8M73.7 42.2h2.5M73.7 52.3h2.5"/>
<path d="M73.7 47.2h2.5M73.7 57.4h2.5M73.7 44.7h2.5M73.7 49.8h2.5M73.7 59.9h2.5M154.9 42.2h2.6M154.9 52.3h2.6M154.9 47.2h2.6M154.9 57.4h2.6M154.9 44.7h2.6M154.9 49.8h2.6M154.9 59.9h2.6"/>
<path d="M195.6 58.7v2.5M210.8 58.7v2.5M251.5 42.2h1.2M251.5 57.4h1.2M251.5 49.8h1.2M257.8 42.2h3.8M257.8 57.4h3.8M257.8 49.8h3.8M34.3 72.6h3.8M34.3 75.2h3.8M38.1 70.1h-3.8v12.7M73.7 70.1h2.5"/>
<path d="M73.7 67.6h2.5M73.7 72.6h2.5M73.7 75.2h2.5M73.7 65h2.5M73.7 62.5h2.5M111.8 73.9v1.3h7.6M111.8 66.3v2.5M115.6 72.6h3.8M119.4 70.1h-3.8v12.7M154.9 70.1h2.6M154.9 67.6h2.6M154.9 72.6h2.6"/>
<path d="M154.9 75.2h2.6M154.9 65h2.6M154.9 62.5h2.6M257.8 65h3.8M229.9 93v3.8M35.6 112h3.8M35.6 117.1h3.8M35.6 114.5h3.8M57.1 100.6v3.8M74.9 112h2.6M74.9 117.1h2.6M74.9 114.5h2.6"/>
<path d="M74.9 119.6h2.6M116.8 112h3.8M116.8 117.1h3.8M116.8 114.5h3.8M138.4 100.6v3.8M156.2 112h2.5M156.2 117.1h2.5M156.2 114.5h2.5M156.2 119.6h2.5M208.3 106.9h3.8M208.3 104.4h3.8M208.3 109.5h3.8"/>
<path d="M247.6 117.1h3.9M247.6 114.5h3.9M247.6 119.6h3.9M74.9 137.4h2.6M74.9 129.8h2.6M74.9 124.7h2.6M74.9 134.9h2.6M74.9 127.2h2.6M74.9 139.9h2.6M74.9 122.2h2.6M156.2 137.4h2.5M156.2 129.8h2.5"/>
<path d="M156.2 124.7h2.5M156.2 134.9h2.5M156.2 127.2h2.5M156.2 139.9h2.5M156.2 122.2h2.5M204.5 138.7v1.2h7.6M204.5 131.1v2.5M247.6 129.8h3.9M247.6 127.2h3.9M247.6 132.3h3.9M31.7 148.8v1.3h7.7M31.7 141.2v2.6"/>
<path d="M35.6 152.6h3.8M39.4 147.6h-3.8v12.7M74.9 142.5h2.6M74.9 147.6h2.6M74.9 150.1h2.6M74.9 152.6h2.6M74.9 145h2.6M105.4 143.8v2.5M105.4 151.4v1.2h15.2M113 148.8v1.3h7.6M113 141.2v2.6M120.6 147.6h-3.8v12.7"/>
<path d="M156.2 142.5h2.5M156.2 147.6h2.5M156.2 150.1h2.5M156.2 152.6h2.5M156.2 145h2.5M208.3 145h3.8M212.1 142.5h-3.8v10.1"/>
</g>
<g fill="none" stroke="#000084" stroke-width=".18">
<path d="M247 108.9l1.3 1.2M247 111.4l1.3 1.2M247 103.8l1.3 1.2M247 106.3l1.3 1.2M248.3 108.9l-1.3 1.2M248.3 111.4l-1.3 1.2M248.3 103.8l-1.3 1.2M248.3 106.3l-1.3 1.2M247 121.6l1.3 1.2M247 134.3l1.3 1.2M247 136.8l1.3 1.2M247 139.3l1.3 1.3"/>
<path d="M248.3 121.6l-1.3 1.2M248.3 134.3l-1.3 1.2M248.3 136.8l-1.3 1.2M248.3 139.3l-1.3 1.3M247 144.4l1.3 1.2M247 141.9l1.3 1.2M248.3 144.4l-1.3 1.2M248.3 141.9l-1.3 1.2"/>
</g>
<g fill="#009600" stroke="#009600" stroke-width=".18">
<circle cx="251.5" cy="34.5" r=".46"/>
<circle cx="251.5" cy="26.9" r=".46"/>
<circle cx="251.5" cy="57.4" r=".46"/>
<circle cx="251.5" cy="49.8" r=".46"/>
<circle cx="251.5" cy="42.2" r=".46"/>
<circle cx="208.3" cy="145" r=".46"/>
<circle cx="34.3" cy="72.6" r=".46"/>
<circle cx="34.3" cy="75.2" r=".46"/>
<circle cx="35.6" cy="152.6" r=".46"/>
<circle cx="115.6" cy="72.6" r=".46"/>
</g>
<use href="#words"/>
</svg>
